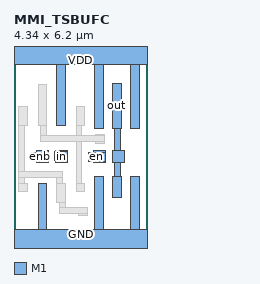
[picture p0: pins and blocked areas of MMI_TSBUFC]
MACRO MMI_TSBUFC
	CLASS CORE ;
	FOREIGN MMI_TSBUFC 0 0 ;
	SIZE 4.34 BY 6.2 ;
	SYMMETRY X Y ;
	SITE CORE1 ;
	PIN out
		DIRECTION output ;
		USE SIGNAL ;
		PORT
			LAYER M1 ;
			RECT 3.215 3.715 3.495 5.185 ;
			LAYER M1 ;
			RECT 3.295 2.98 3.485 3.715 ;
			LAYER M1 ;
			RECT 3.22 2.6 3.6 2.98 ;
			LAYER M1 ;
			RECT 3.295 2.14 3.485 2.6 ;
			LAYER M1 ;
			RECT 3.215 1.44 3.495 2.14 ;
		END
		AntennaDiffArea 1.0164 ;
	END out
	PIN GND
		DIRECTION inout ;
		USE GROUND ;
		PORT
			LAYER M1 ;
			RECT 0.795 0.42 1.075 1.915 ;
			LAYER M1 ;
			RECT 2.625 0.42 2.905 2.14 ;
			LAYER M1 ;
			RECT 3.805 0.42 4.085 2.14 ;
			LAYER M1 ;
			RECT 0 -0.42 4.34 0.42 ;
		END
	END GND
	PIN enb
		DIRECTION input ;
		USE SIGNAL ;
		PORT
			LAYER M1 ;
			RECT 0.74 2.93 1.12 2.98 ;
			LAYER M1 ;
			RECT 0.555 2.65 1.12 2.93 ;
			LAYER M1 ;
			RECT 0.74 2.6 1.12 2.65 ;
		END
		AntennaGateArea 0.15825 ;
	END enb
	PIN VDD
		DIRECTION inout ;
		USE POWER ;
		PORT
			LAYER M1 ;
			RECT 0 5.78 4.34 6.62 ;
			LAYER M1 ;
			RECT 1.385 3.8 1.665 5.78 ;
			LAYER M1 ;
			RECT 2.625 3.715 2.905 5.78 ;
			LAYER M1 ;
			RECT 3.805 3.715 4.085 5.78 ;
		END
	END VDD
	PIN en
		DIRECTION input ;
		USE SIGNAL ;
		PORT
			LAYER M1 ;
			RECT 2.6 2.92 2.98 2.98 ;
			LAYER M1 ;
			RECT 2.425 2.64 2.98 2.92 ;
			LAYER M1 ;
			RECT 2.6 2.6 2.98 2.64 ;
		END
		AntennaGateArea 0.15825 ;
	END en
	PIN in
		DIRECTION input ;
		USE SIGNAL ;
		PORT
			LAYER M1 ;
			RECT 1.36 2.94 1.74 2.98 ;
			LAYER M1 ;
			RECT 1.33 2.66 1.74 2.94 ;
			LAYER M1 ;
			RECT 1.36 2.6 1.74 2.66 ;
		END
		AntennaGateArea 0.31725 ;
	END in
	OBS
		LAYER M1 ;
		RECT 0.16 3.8 0.44 4.435 ;
		LAYER M1 ;
		RECT 0.795 3.8 1.075 5.14 ;
		LAYER M1 ;
		RECT 2.025 3.8 2.305 4.435 ;
		LAYER M1 ;
		RECT 0.16 2.31 0.35 3.8 ;
		LAYER M1 ;
		RECT 0.88 3.465 1.075 3.8 ;
		LAYER M1 ;
		RECT 2.025 3.465 2.215 3.8 ;
		LAYER M1 ;
		RECT 2.67 3.465 2.95 3.51 ;
		LAYER M1 ;
		RECT 0.88 3.27 2.95 3.465 ;
		LAYER M1 ;
		RECT 0.16 2.115 1.58 2.31 ;
		LAYER M1 ;
		RECT 0.16 1.915 0.35 2.115 ;
		LAYER M1 ;
		RECT 1.385 1.915 1.58 2.115 ;
		LAYER M1 ;
		RECT 2.025 1.92 2.215 3.27 ;
		LAYER M1 ;
		RECT 2.67 3.23 2.95 3.27 ;
		LAYER M1 ;
		RECT 0.16 1.635 0.44 1.915 ;
		LAYER M1 ;
		RECT 1.385 1.28 1.665 1.915 ;
		LAYER M1 ;
		RECT 2.025 1.64 2.305 1.92 ;
		LAYER M1 ;
		RECT 1.475 1.13 1.665 1.28 ;
		LAYER M1 ;
		RECT 1.475 0.935 2.385 1.13 ;
		LAYER M1 ;
		RECT 2.105 0.85 2.385 0.935 ;
	END
END MMI_TSBUFC
